VERSION 5.4 ;
NAMESCASESENSITIVE ON ;
BUSBITCHARS "[]" ;
DIVIDERCHAR "/" ;
UNITS
  DATABASE MICRONS 2000 ;
END UNITS
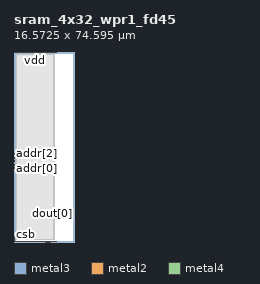
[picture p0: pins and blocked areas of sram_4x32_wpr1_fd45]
MACRO sram_4x32_wpr1_fd45
   CLASS BLOCK ;
   SIZE 16.5725 BY 74.5950 ;
   SYMMETRY X Y R90 ;
   PIN addr[0]
      DIRECTION INPUT ;
      PORT
         LAYER metal3 ;
         RECT 0.0000 28.7575 0.1600 29.2575 ;
      END
   END addr[0]
   PIN addr[1]
      DIRECTION INPUT ;
      PORT
         LAYER metal3 ;
         RECT 0.0000 30.1225 0.1600 30.6225 ;
      END
   END addr[1]
   PIN addr[2]
      DIRECTION INPUT ;
      PORT
         LAYER metal3 ;
         RECT 0.0000 31.4875 0.1600 31.9875 ;
      END
   END addr[2]
   PIN addr[3]
      DIRECTION INPUT ;
      PORT
         LAYER metal3 ;
         RECT 0.0000 32.8525 0.1600 33.3525 ;
      END
   END addr[3]
   PIN addr[4]
      DIRECTION INPUT ;
      PORT
         LAYER metal3 ;
         RECT 0.0000 34.2175 0.1600 34.7175 ;
      END
   END addr[4]
   PIN clk
      DIRECTION INPUT ;
      PORT
         LAYER metal2 ;
         RECT 0.0000 0.2425 0.1600 0.7425 ;
      END
   END clk
   PIN csb
      DIRECTION INPUT ;
      PORT
         LAYER metal2 ;
         RECT 0.0000 0.9925 0.1600 1.4925 ;
      END
   END csb
   PIN din[0]
      DIRECTION INPUT ;
      PORT
         LAYER metal2 ;
         RECT 12.4650 0.0000 12.9650 0.1600 ;
      END
   END din[0]
   PIN din[1]
      DIRECTION INPUT ;
      PORT
         LAYER metal2 ;
         RECT 12.8940 0.0000 13.3940 0.1600 ;
      END
   END din[1]
   PIN din[2]
      DIRECTION INPUT ;
      PORT
         LAYER metal2 ;
         RECT 13.4660 0.0000 13.9660 0.1600 ;
      END
   END din[2]
   PIN din[3]
      DIRECTION INPUT ;
      PORT
         LAYER metal2 ;
         RECT 13.8950 0.0000 14.3950 0.1600 ;
      END
   END din[3]
   PIN dout[0]
      DIRECTION OUTPUT ;
      PORT
         LAYER metal3 ;
         RECT 16.4125 10.9700 16.5725 11.4700 ;
      END
   END dout[0]
   PIN dout[1]
      DIRECTION OUTPUT ;
      PORT
         LAYER metal3 ;
         RECT 16.4125 11.5400 16.5725 12.0400 ;
      END
   END dout[1]
   PIN dout[2]
      DIRECTION OUTPUT ;
      PORT
         LAYER metal3 ;
         RECT 16.4125 12.1100 16.5725 12.6100 ;
      END
   END dout[2]
   PIN dout[3]
      DIRECTION OUTPUT ;
      PORT
         LAYER metal3 ;
         RECT 16.4125 12.6800 16.5725 13.1800 ;
      END
   END dout[3]
   PIN gnd
      DIRECTION INOUT ;
      USE GROUND ;
      SHAPE ABUTMENT ;
      PORT
         LAYER metal4 ;
         RECT 0.0000 0.0500 16.5725 0.2000 ;
      END
   END gnd
   PIN vdd
      DIRECTION INOUT ;
      USE POWER ;
      SHAPE ABUTMENT ;
      PORT
         LAYER metal4 ;
         RECT 0.0000 74.3950 16.5725 74.5450 ;
      END
   END vdd
   PIN web
      DIRECTION INPUT ;
      PORT
         LAYER metal2 ;
         RECT 0.0000 1.7425 0.1600 2.2425 ;
      END
   END web
   OBS
      LAYER metal1 ;
         RECT 0.8000 0.8000 15.7725 73.7950 ;
      LAYER metal2 ;
         RECT 0.8000 0.8000 15.7725 73.7950 ;
      LAYER metal3 ;
         RECT 0.8000 0.8000 15.7725 73.7950 ;
      LAYER metal4 ;
         RECT 1.1200 1.1200 15.4525 73.4750 ;
   END
END sram_4x32_wpr1_fd45
END LIBRARY
